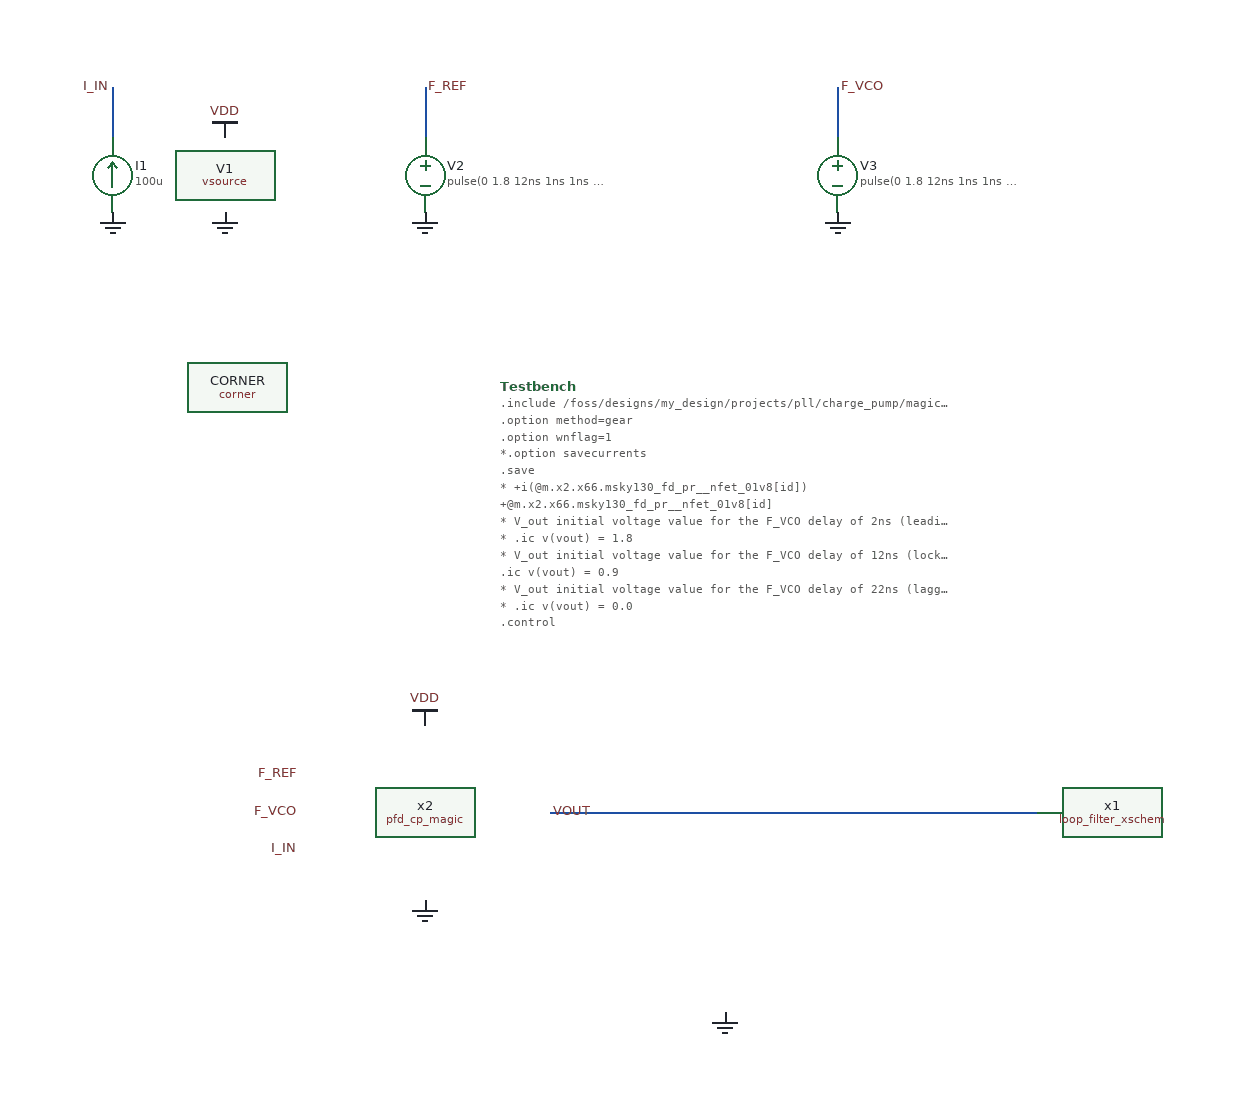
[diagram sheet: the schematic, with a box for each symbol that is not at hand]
v {xschem version=3.4.6 file_version=1.2}
G {}
K {}
V {}
S {}
E {}
B 2 3410 -4250 4770 -3590 {flags=graph
y1=0
y2=1.8
ypos1=0
ypos2=2
divy=5
subdivy=1
unity=1
x1=0
x2=2e-08
divx=5
subdivx=1
xlabmag=1.0
ylabmag=1.0


dataset=0
unitx=1
logx=0
logy=0








linewidth_mult=3







autoload=0
sim_type=tran
color="6 7"
node="f_ref
f_vco"}
B 2 3410 -2860 4790 -2180 {flags=graph
y1=0
y2=0.01
ypos1=0
ypos2=2
divy=5
subdivy=1
unity=1
x1=0
x2=2e-08
divx=5
subdivx=1
xlabmag=1.0
ylabmag=1.0


dataset=0
unitx=1
logx=0
logy=0








linewidth_mult=5





color="6 5"
node="up_pfd_b
down_pfd_b"}
B 2 3410 -3570 4790 -2870 {flags=graph
y1=0
y2=0.01
ypos1=0
ypos2=2
divy=5
subdivy=1
unity=1
x1=0
x2=2e-08
divx=5
subdivx=1
xlabmag=1.0
ylabmag=1.0


dataset=0
unitx=1
logx=0
logy=0








linewidth_mult=5

color="6 5"
node="up_pfd
down_pfd"}
B 2 3410 -2160 4790 -1480 {flags=graph
y1=0
y2=0.01
ypos1=0
ypos2=2
divy=5
subdivy=1
unity=1
x1=0
x2=2e-08
divx=5
subdivx=1
xlabmag=1.0
ylabmag=1.0


dataset=0
unitx=1
logx=0
logy=0








linewidth_mult=5





color="6 5"
node="up
down_b"}
B 2 3410 -1460 4790 -780 {flags=graph
y1=0
y2=0.01
ypos1=0
ypos2=2
divy=5
subdivy=1
unity=1
x1=0
x2=2e-08
divx=5
subdivx=1
xlabmag=1.0
ylabmag=1.0


dataset=0
unitx=1
logx=0
logy=0








linewidth_mult=5





color="6 5"
node="up_b
down"}
B 2 1860 -1670 3220 -1000 {flags=graph
y1=1.7
y2=1.9
ypos1=0
ypos2=2
divy=5
subdivy=1
unity=1
x1=0
x2=2e-08
divx=5
subdivx=1
xlabmag=1.0
ylabmag=1.0


dataset=0
unitx=1
logx=0
logy=0








linewidth_mult=7




color="5 5 5 5 5 5 5 5 5 5 5 5 5 5 5 5 5 5 5 5 5 5 5 5 5 5 5 5 5 5 5 5 5 5 5 5 5 5 5 5 5 5 5 5 5 5 5 5 5 5 5 5 5 5 5 5 5 5 5 5 5 5 5 5 5 5 5 5 5 5 5 5 5 5 5 5 5 5 5 5 5 5 5 5 5 5 5 5 5 5 5 5 5 5 5 5 5 5 5 5 5 5 5 5 5 5 5 5 5 5 5 5 5 5 5 5 5 5 5 5 5 5 5 5 5 5 5 5 5 5 5 5 5 5 5 5 5 5 5 5 5 5 5 5 5 5 5 5 5 5 5 5 5 5 5 5 5 5 5 5 5 5 5 5 5 5 5 5 5 5 5 5 5 5 5 5 5 5 5 5 5 5 5 5 5 5 5 5 5 5 5 5 5 5 5 5 5 5 5 5 5 5 5 5 5 5 5 5 5 5 5 5 5 5 5 5 5 5 5 5 5 5 5 5 5 5 5 5 5 5 5 5 5 5 5 5 5 5 5 5 5 5 5 5 5 5 5 5 5 5 5 5 5 5 5 5 5 5 5 5 5 5 5 5 5 5 5 5 5 5 5 5 5 5 5 5 5 5 5 5 5 5 5 5 5 5 5 5 5 5 5 5 5 5 5 5 5 5 5 5 5 5 5 5 5 5 5 5 5 5 5 5 5 5 5 5 5 5 5 5 5 5 5 5 5 5 5 5 5 5 5 5 5 5 5 5 5 5 5 5 5 5 5 5 5 5 5 5 5 5 5 5 5 5 5 5 5 5 5 5 5 5 5 5 5 5 5 5 5 5 5 5 5 5 5 5 5 5 5 5 5 5 5 5 5 5 5 5 5 5 5 5 5 5 5 5 5 5 5 5 5 5 5 5 5 5 5 5 5 5 5 5 5 5 5 5 5 5 5 5 5 5 5 5 5 5 5 5 5 5 5 5 5 5 5 5 5 5 5 5 5 5 5 5 5 5 5 5 5 5 5 5 5 5 5 5 5 5 5 5 5 5 5 5 5 5 5 5 5 5 5 5 5 5 5 5 5 5 5 5 5 5 5 5 5 5 5 5 5 5 5 5 5 5 5 5 5 5 5 5 5 5 5 5 5 5 5 5 5 5 5 5 5 5 5 5 5 5 5 5 5 5 5 5 5 5 5 5 5 5 5 5 5 5 5 5 5 5 5 5 5 5 5 5 5 5 5 5 5 5 5 5 5 5 5 5 5 5 5 5 5 5 5 5 5 5 5 5 5 5 5 5 5 5 5 5 5 5 5 5 5 5 5 5 5 5 5 5 5 5 5 5 5 5 5 5 5 5 5 5 5 5 5 5 5 5 5 5 5 5 5 5 5 5 5 5 5 5 5 5 5 5 5 5 5 5 5 5 5 5 5 5 5 5 5 5"
node="x2.vdda.t129
x2.vdda.t128
x2.vdda.t127
x2.vdda.t126
x2.vdda.t125
x2.vdda.t124
x2.vdda.t123
x2.vdda.t122
x2.vdda.t121
x2.vdda.t120
x2.vdda.t119
x2.vdda.t118
x2.vdda.t117
x2.vdda.t116
x2.vdda.t115
x2.vdda.t114
x2.vdda.t113
x2.vdda.t112
x2.vdda.t111
x2.vdda.t110
x2.vdda.t109
x2.vdda.t108
x2.vdda.t107
x2.vdda.t106
x2.vdda.t105
x2.vdda.t104
x2.vdda.t103
x2.vdda.t102
x2.vdda.t101
x2.vdda.t100
x2.vdda.t99
x2.vdda.t98
x2.vdda.t97
x2.vdda.t96
x2.vdda.t95
x2.vdda.t94
x2.vdda.t93
x2.vdda.t92
x2.vdda.t91
x2.vdda.t90
x2.vdda.t89
x2.vdda.t88
x2.vdda.t87
x2.vdda.t86
x2.vdda.t85
x2.vdda.t84
x2.vdda.t83
x2.vdda.t82
x2.vdda.t81
x2.vdda.t80
x2.vdda.t79
x2.vdda.t78
x2.vdda.t77
x2.vdda.t76
x2.vdda.t75
x2.vdda.t74
x2.vdda.t73
x2.vdda.t72
x2.vdda.t71
x2.vdda.t70
x2.vdda.t69
x2.vdda.t68
x2.vdda.t67
x2.vdda.t66
x2.vdda.t65
x2.vdda.t64
x2.vdda.t63
x2.vdda.t62
x2.vdda.t61
x2.vdda.t60
x2.vdda.t59
x2.vdda.t58
x2.vdda.t57
x2.vdda.t56
x2.vdda.t55
x2.vdda.t54
x2.vdda.t53
x2.vdda.t52
x2.vdda.t51
x2.vdda.t50
x2.vdda.t49
x2.vdda.t48
x2.vdda.t47
x2.vdda.t46
x2.vdda.t45
x2.vdda.t44
x2.vdda.t43
x2.vdda.t42
x2.vdda.t41
x2.vdda.t40
x2.vdda.t39
x2.vdda.t38
x2.vdda.t37
x2.vdda.t36
x2.vdda.t35
x2.vdda.t34
x2.vdda.t33
x2.vdda.t32
x2.vdda.t31
x2.vdda.t30
x2.vdda.t29
x2.vdda.t28
x2.vdda.t27
x2.vdda.t26
x2.vdda.t25
x2.vdda.t24
x2.vdda.t23
x2.vdda.t22
x2.vdda.t21
x2.vdda.t20
x2.vdda.t19
x2.vdda.t18
x2.vdda.t17
x2.vdda.t16
x2.vdda.t15
x2.vdda.t14
x2.vdda.t13
x2.vdda.t12
x2.vdda.t11
x2.vdda.t10
x2.vdda.t9
x2.vdda.t8
x2.vdda.t7
x2.vdda.t6
x2.vdda.t5
x2.vdda.t4
x2.vdda.t3
x2.vdda.t2
x2.vdda.t1
x2.vdda.t0
x2.vdda.n505
x2.vdda.n504
x2.vdda.n503
x2.vdda.n502
x2.vdda.n501
x2.vdda.n500
x2.vdda.n499
x2.vdda.n498
x2.vdda.n497
x2.vdda.n496
x2.vdda.n495
x2.vdda.n494
x2.vdda.n493
x2.vdda.n492
x2.vdda.n491
x2.vdda.n490
x2.vdda.n489
x2.vdda.n488
x2.vdda.n487
x2.vdda.n486
x2.vdda.n485
x2.vdda.n484
x2.vdda.n483
x2.vdda.n482
x2.vdda.n481
x2.vdda.n480
x2.vdda.n479
x2.vdda.n478
x2.vdda.n477
x2.vdda.n476
x2.vdda.n475
x2.vdda.n474
x2.vdda.n473
x2.vdda.n472
x2.vdda.n471
x2.vdda.n470
x2.vdda.n469
x2.vdda.n468
x2.vdda.n467
x2.vdda.n466
x2.vdda.n465
x2.vdda.n464
x2.vdda.n463
x2.vdda.n462
x2.vdda.n461
x2.vdda.n460
x2.vdda.n459
x2.vdda.n458
x2.vdda.n457
x2.vdda.n456
x2.vdda.n455
x2.vdda.n454
x2.vdda.n453
x2.vdda.n452
x2.vdda.n451
x2.vdda.n450
x2.vdda.n449
x2.vdda.n448
x2.vdda.n447
x2.vdda.n446
x2.vdda.n445
x2.vdda.n444
x2.vdda.n443
x2.vdda.n442
x2.vdda.n441
x2.vdda.n440
x2.vdda.n439
x2.vdda.n438
x2.vdda.n437
x2.vdda.n436
x2.vdda.n435
x2.vdda.n434
x2.vdda.n433
x2.vdda.n432
x2.vdda.n431
x2.vdda.n430
x2.vdda.n429
x2.vdda.n428
x2.vdda.n427
x2.vdda.n426
x2.vdda.n425
x2.vdda.n424
x2.vdda.n423
x2.vdda.n422
x2.vdda.n421
x2.vdda.n420
x2.vdda.n419
x2.vdda.n418
x2.vdda.n417
x2.vdda.n416
x2.vdda.n415
x2.vdda.n414
x2.vdda.n413
x2.vdda.n412
x2.vdda.n411
x2.vdda.n410
x2.vdda.n409
x2.vdda.n408
x2.vdda.n407
x2.vdda.n406
x2.vdda.n405
x2.vdda.n404
x2.vdda.n403
x2.vdda.n402
x2.vdda.n401
x2.vdda.n400
x2.vdda.n399
x2.vdda.n398
x2.vdda.n397
x2.vdda.n396
x2.vdda.n395
x2.vdda.n394
x2.vdda.n393
x2.vdda.n392
x2.vdda.n391
x2.vdda.n390
x2.vdda.n389
x2.vdda.n388
x2.vdda.n387
x2.vdda.n386
x2.vdda.n385
x2.vdda.n384
x2.vdda.n383
x2.vdda.n382
x2.vdda.n381
x2.vdda.n380
x2.vdda.n379
x2.vdda.n378
x2.vdda.n377
x2.vdda.n376
x2.vdda.n375
x2.vdda.n374
x2.vdda.n373
x2.vdda.n372
x2.vdda.n371
x2.vdda.n370
x2.vdda.n369
x2.vdda.n368
x2.vdda.n367
x2.vdda.n366
x2.vdda.n365
x2.vdda.n364
x2.vdda.n363
x2.vdda.n362
x2.vdda.n361
x2.vdda.n360
x2.vdda.n359
x2.vdda.n358
x2.vdda.n357
x2.vdda.n356
x2.vdda.n355
x2.vdda.n354
x2.vdda.n353
x2.vdda.n352
x2.vdda.n351
x2.vdda.n350
x2.vdda.n349
x2.vdda.n348
x2.vdda.n347
x2.vdda.n346
x2.vdda.n345
x2.vdda.n344
x2.vdda.n343
x2.vdda.n342
x2.vdda.n341
x2.vdda.n340
x2.vdda.n339
x2.vdda.n338
x2.vdda.n337
x2.vdda.n336
x2.vdda.n335
x2.vdda.n334
x2.vdda.n333
x2.vdda.n332
x2.vdda.n331
x2.vdda.n330
x2.vdda.n329
x2.vdda.n328
x2.vdda.n327
x2.vdda.n326
x2.vdda.n325
x2.vdda.n324
x2.vdda.n323
x2.vdda.n322
x2.vdda.n321
x2.vdda.n320
x2.vdda.n319
x2.vdda.n318
x2.vdda.n317
x2.vdda.n316
x2.vdda.n315
x2.vdda.n314
x2.vdda.n313
x2.vdda.n312
x2.vdda.n311
x2.vdda.n310
x2.vdda.n309
x2.vdda.n308
x2.vdda.n307
x2.vdda.n306
x2.vdda.n305
x2.vdda.n304
x2.vdda.n303
x2.vdda.n302
x2.vdda.n301
x2.vdda.n300
x2.vdda.n299
x2.vdda.n298
x2.vdda.n297
x2.vdda.n296
x2.vdda.n295
x2.vdda.n294
x2.vdda.n293
x2.vdda.n292
x2.vdda.n291
x2.vdda.n290
x2.vdda.n289
x2.vdda.n288
x2.vdda.n287
x2.vdda.n286
x2.vdda.n285
x2.vdda.n284
x2.vdda.n283
x2.vdda.n282
x2.vdda.n281
x2.vdda.n280
x2.vdda.n279
x2.vdda.n278
x2.vdda.n277
x2.vdda.n276
x2.vdda.n275
x2.vdda.n274
x2.vdda.n273
x2.vdda.n272
x2.vdda.n271
x2.vdda.n270
x2.vdda.n269
x2.vdda.n268
x2.vdda.n267
x2.vdda.n266
x2.vdda.n265
x2.vdda.n264
x2.vdda.n263
x2.vdda.n262
x2.vdda.n261
x2.vdda.n260
x2.vdda.n259
x2.vdda.n258
x2.vdda.n257
x2.vdda.n256
x2.vdda.n255
x2.vdda.n254
x2.vdda.n253
x2.vdda.n252
x2.vdda.n251
x2.vdda.n250
x2.vdda.n249
x2.vdda.n248
x2.vdda.n247
x2.vdda.n246
x2.vdda.n245
x2.vdda.n244
x2.vdda.n243
x2.vdda.n242
x2.vdda.n241
x2.vdda.n240
x2.vdda.n239
x2.vdda.n238
x2.vdda.n237
x2.vdda.n236
x2.vdda.n235
x2.vdda.n234
x2.vdda.n233
x2.vdda.n232
x2.vdda.n231
x2.vdda.n230
x2.vdda.n229
x2.vdda.n228
x2.vdda.n227
x2.vdda.n226
x2.vdda.n225
x2.vdda.n224
x2.vdda.n223
x2.vdda.n222
x2.vdda.n221
x2.vdda.n220
x2.vdda.n219
x2.vdda.n218
x2.vdda.n217
x2.vdda.n216
x2.vdda.n215
x2.vdda.n214
x2.vdda.n213
x2.vdda.n212
x2.vdda.n211
x2.vdda.n210
x2.vdda.n209
x2.vdda.n208
x2.vdda.n207
x2.vdda.n206
x2.vdda.n205
x2.vdda.n204
x2.vdda.n203
x2.vdda.n202
x2.vdda.n201
x2.vdda.n200
x2.vdda.n199
x2.vdda.n198
x2.vdda.n197
x2.vdda.n196
x2.vdda.n195
x2.vdda.n194
x2.vdda.n193
x2.vdda.n192
x2.vdda.n191
x2.vdda.n190
x2.vdda.n189
x2.vdda.n188
x2.vdda.n187
x2.vdda.n186
x2.vdda.n185
x2.vdda.n184
x2.vdda.n183
x2.vdda.n182
x2.vdda.n181
x2.vdda.n180
x2.vdda.n179
x2.vdda.n178
x2.vdda.n177
x2.vdda.n176
x2.vdda.n175
x2.vdda.n174
x2.vdda.n173
x2.vdda.n172
x2.vdda.n171
x2.vdda.n170
x2.vdda.n169
x2.vdda.n168
x2.vdda.n167
x2.vdda.n166
x2.vdda.n165
x2.vdda.n164
x2.vdda.n163
x2.vdda.n162
x2.vdda.n161
x2.vdda.n160
x2.vdda.n159
x2.vdda.n158
x2.vdda.n157
x2.vdda.n156
x2.vdda.n155
x2.vdda.n154
x2.vdda.n153
x2.vdda.n152
x2.vdda.n151
x2.vdda.n150
x2.vdda.n149
x2.vdda.n148
x2.vdda.n147
x2.vdda.n146
x2.vdda.n145
x2.vdda.n144
x2.vdda.n143
x2.vdda.n142
x2.vdda.n141
x2.vdda.n140
x2.vdda.n139
x2.vdda.n138
x2.vdda.n137
x2.vdda.n136
x2.vdda.n135
x2.vdda.n134
x2.vdda.n133
x2.vdda.n132
x2.vdda.n131
x2.vdda.n130
x2.vdda.n129
x2.vdda.n128
x2.vdda.n127
x2.vdda.n126
x2.vdda.n125
x2.vdda.n124
x2.vdda.n123
x2.vdda.n122
x2.vdda.n121
x2.vdda.n120
x2.vdda.n119
x2.vdda.n118
x2.vdda.n117
x2.vdda.n116
x2.vdda.n115
x2.vdda.n114
x2.vdda.n113
x2.vdda.n112
x2.vdda.n111
x2.vdda.n110
x2.vdda.n109
x2.vdda.n108
x2.vdda.n107
x2.vdda.n106
x2.vdda.n105
x2.vdda.n104
x2.vdda.n103
x2.vdda.n102
x2.vdda.n101
x2.vdda.n100
x2.vdda.n99
x2.vdda.n98
x2.vdda.n97
x2.vdda.n96
x2.vdda.n95
x2.vdda.n94
x2.vdda.n93
x2.vdda.n92
x2.vdda.n91
x2.vdda.n90
x2.vdda.n89
x2.vdda.n88
x2.vdda.n87
x2.vdda.n86
x2.vdda.n85
x2.vdda.n84
x2.vdda.n83
x2.vdda.n82
x2.vdda.n81
x2.vdda.n80
x2.vdda.n79
x2.vdda.n78
x2.vdda.n77
x2.vdda.n76
x2.vdda.n75
x2.vdda.n74
x2.vdda.n73
x2.vdda.n72
x2.vdda.n71
x2.vdda.n70
x2.vdda.n69
x2.vdda.n68
x2.vdda.n67
x2.vdda.n66
x2.vdda.n65
x2.vdda.n64
x2.vdda.n63
x2.vdda.n62
x2.vdda.n61
x2.vdda.n60
x2.vdda.n59
x2.vdda.n58
x2.vdda.n57
x2.vdda.n56
x2.vdda.n55
x2.vdda.n54
x2.vdda.n53
x2.vdda.n52
x2.vdda.n51
x2.vdda.n50
x2.vdda.n49
x2.vdda.n48
x2.vdda.n47
x2.vdda.n46
x2.vdda.n45
x2.vdda.n44
x2.vdda.n43
x2.vdda.n42
x2.vdda.n41
x2.vdda.n40
x2.vdda.n39
x2.vdda.n38
x2.vdda.n37
x2.vdda.n36
x2.vdda.n35
x2.vdda.n34
x2.vdda.n33
x2.vdda.n32
x2.vdda.n31
x2.vdda.n30
x2.vdda.n29
x2.vdda.n28
x2.vdda.n27
x2.vdda.n26
x2.vdda.n25
x2.vdda.n24
x2.vdda.n23
x2.vdda.n22
x2.vdda.n21
x2.vdda.n20
x2.vdda.n19
x2.vdda.n18
x2.vdda.n17
x2.vdda.n16
x2.vdda.n15
x2.vdda.n14
x2.vdda.n13
x2.vdda.n12
x2.vdda.n11
x2.vdda.n10
x2.vdda.n9
x2.vdda.n8
x2.vdda.n7
x2.vdda.n6
x2.vdda.n5
x2.vdda.n4
x2.vdda.n3
x2.vdda.n2
x2.vdda.n1
x2.vdda.n0"}
B 2 1860 -2370 3220 -1700 {flags=graph
y1=-0.045
y2=0.064
ypos1=0
ypos2=2
divy=5
subdivy=1
unity=1
x1=0
x2=2e-08
divx=5
subdivx=1
xlabmag=1.0
ylabmag=1.0


dataset=0
unitx=1
logx=0
logy=0








linewidth_mult=7




color="5 5 5 5 5 5 5 5 5 5 5 5 5 5 5 5 5 5 5 5 5 5 5 5 5 5 5 5 5 5 5 5 5 5 5 5 5 5 5 5 5 5 5 5 5 5 5 5 5 5 5 5 5 5 5 5 5 5 5 5 5 5 5 5 5 5 5 5 5 5 5 5 5 5 5 5 5 5 5 5 5 5 5 5 5 5 5 5 5 5 5 5 5 5 5 5 5 5 5 5 5 5 5 5 5 5 5 5 5 5 5 5 5 5 5 5 5 5 5 5 5 5 5 5 5 5 5 5 5 5 5 5 5 5 5 5 5 5 5 5 5 5 5 5 5 5 5 5 5 5 5 5 5 5 5 5 5 5 5 5 5 5 5 5 5 5 5 5 5 5 5 5 5 5 5 5 5 5 5 5 5 5 5 5 5 5 5 5 5 5 5 5 5 5 5 5 5 5 5 5 5 5 5 5 5 5 5 5 5 5 5 5 5 5 5 5 5 5 5 5 5 5 5 5 5 5 5 5 5 5 5 5 5 5 5 5 5 5 5 5 5 5 5 5 5 5 5 5 5 5 5 5 5 5 5 5 5 5 5 5 5 5 5 5 5 5 5 5 5 5 5 5 5 5 5 5 5 5 5 5 5 5 5 5 5 5 5 5 5 5 5 5 5 5 5 5 5 5 5 5 5 5 5 5 5 5 5 5 5 5 5 5 5 5 5 5 5 5 5 5 5 5 5 5 5 5 5 5 5 5 5 5 5 5 5 5 5 5 5 5 5 5 5 5 5 5 5 5 5 5 5 5 5 5 5 5 5 5 5 5 5 5 5 5 5 5 5 5 5 5 5 5 5 5 5 5 5 5 5 5 5 5 5 5 5 5 5 5 5 5 5 5 5 5 5 5 5 5 5 5 5 5 5 5 5 5 5 5 5 5 5 5 5 5 5 5 5 5 5 5 5 5 5 5 5 5 5 5 5 5 5 5 5 5 5 5 5 5 5 5 5 5 5 5 5 5 5 5 5 5 5 5 5 5 5 5 5 5 5 5 5 5 5 5 5 5 5 5 5 5 5 5 5 5 5 5 5 5 5 5 5 5 5 5 5 5 5 5 5 5 5 5 5 5 5 5 5 5 5 5 5 5 5 5 5 5 5 5 5 5 5 5 5 5 5 5 5 5 5 5 5 5 5 5 5 5 5 5 5 5 5 5 5 5 5 5 5 5 5 5 5 5 5 5 5 5 5 5 5 5 5 5 5 5 5 5 5 5 5 5 5 5 5 5 5 5 5 5 5 5 5 5 5 5 5 5 5 5 5 5 5 5 5 5 5 5 5 5 5 5 5 5 5 5 5 5 5 5 5 5 5 5 5"
node="x2.gnda.t155
x2.gnda.t154
x2.gnda.t153
x2.gnda.t152
x2.gnda.t151
x2.gnda.t150
x2.gnda.t149
x2.gnda.t148
x2.gnda.t147
x2.gnda.t146
x2.gnda.t145
x2.gnda.t144
x2.gnda.t143
x2.gnda.t142
x2.gnda.t141
x2.gnda.t140
x2.gnda.t139
x2.gnda.t138
x2.gnda.t137
x2.gnda.t136
x2.gnda.t135
x2.gnda.t134
x2.gnda.t133
x2.gnda.t132
x2.gnda.t131
x2.gnda.t130
x2.gnda.t129
x2.gnda.t128
x2.gnda.t127
x2.gnda.t126
x2.gnda.t125
x2.gnda.t124
x2.gnda.t123
x2.gnda.t122
x2.gnda.t121
x2.gnda.t120
x2.gnda.t119
x2.gnda.t118
x2.gnda.t117
x2.gnda.t116
x2.gnda.t115
x2.gnda.t114
x2.gnda.t113
x2.gnda.t112
x2.gnda.t111
x2.gnda.t110
x2.gnda.t109
x2.gnda.t108
x2.gnda.t107
x2.gnda.t106
x2.gnda.t105
x2.gnda.t104
x2.gnda.t103
x2.gnda.t102
x2.gnda.t101
x2.gnda.t100
x2.gnda.t99
x2.gnda.t98
x2.gnda.t97
x2.gnda.t96
x2.gnda.t95
x2.gnda.t94
x2.gnda.t93
x2.gnda.t92
x2.gnda.t91
x2.gnda.t90
x2.gnda.t89
x2.gnda.t88
x2.gnda.t87
x2.gnda.t86
x2.gnda.t85
x2.gnda.t84
x2.gnda.t83
x2.gnda.t82
x2.gnda.t81
x2.gnda.t80
x2.gnda.t79
x2.gnda.t78
x2.gnda.t77
x2.gnda.t76
x2.gnda.t75
x2.gnda.t74
x2.gnda.t73
x2.gnda.t72
x2.gnda.t71
x2.gnda.t70
x2.gnda.t69
x2.gnda.t68
x2.gnda.t67
x2.gnda.t66
x2.gnda.t65
x2.gnda.t64
x2.gnda.t63
x2.gnda.t62
x2.gnda.t61
x2.gnda.t60
x2.gnda.t59
x2.gnda.t58
x2.gnda.t57
x2.gnda.t56
x2.gnda.t55
x2.gnda.t54
x2.gnda.t53
x2.gnda.t52
x2.gnda.t51
x2.gnda.t50
x2.gnda.t49
x2.gnda.t48
x2.gnda.t47
x2.gnda.t46
x2.gnda.t45
x2.gnda.t44
x2.gnda.t43
x2.gnda.t42
x2.gnda.t41
x2.gnda.t40
x2.gnda.t39
x2.gnda.t38
x2.gnda.t37
x2.gnda.t36
x2.gnda.t35
x2.gnda.t34
x2.gnda.t33
x2.gnda.t32
x2.gnda.t31
x2.gnda.t30
x2.gnda.t29
x2.gnda.t28
x2.gnda.t27
x2.gnda.t26
x2.gnda.t25
x2.gnda.t24
x2.gnda.t23
x2.gnda.t22
x2.gnda.t21
x2.gnda.t20
x2.gnda.t19
x2.gnda.t18
x2.gnda.t17
x2.gnda.t16
x2.gnda.t15
x2.gnda.t14
x2.gnda.t13
x2.gnda.t12
x2.gnda.t11
x2.gnda.t10
x2.gnda.t9
x2.gnda.t8
x2.gnda.t7
x2.gnda.t6
x2.gnda.t5
x2.gnda.t4
x2.gnda.t3
x2.gnda.t2
x2.gnda.t1
x2.gnda.t0
x2.gnda.n446
x2.gnda.n445
x2.gnda.n444
x2.gnda.n443
x2.gnda.n442
x2.gnda.n441
x2.gnda.n440
x2.gnda.n439
x2.gnda.n438
x2.gnda.n437
x2.gnda.n436
x2.gnda.n435
x2.gnda.n434
x2.gnda.n433
x2.gnda.n432
x2.gnda.n431
x2.gnda.n430
x2.gnda.n429
x2.gnda.n428
x2.gnda.n427
x2.gnda.n426
x2.gnda.n425
x2.gnda.n424
x2.gnda.n423
x2.gnda.n422
x2.gnda.n421
x2.gnda.n420
x2.gnda.n419
x2.gnda.n418
x2.gnda.n417
x2.gnda.n416
x2.gnda.n415
x2.gnda.n414
x2.gnda.n413
x2.gnda.n412
x2.gnda.n411
x2.gnda.n410
x2.gnda.n409
x2.gnda.n408
x2.gnda.n407
x2.gnda.n406
x2.gnda.n405
x2.gnda.n404
x2.gnda.n403
x2.gnda.n402
x2.gnda.n401
x2.gnda.n400
x2.gnda.n399
x2.gnda.n398
x2.gnda.n397
x2.gnda.n396
x2.gnda.n395
x2.gnda.n394
x2.gnda.n393
x2.gnda.n392
x2.gnda.n391
x2.gnda.n390
x2.gnda.n389
x2.gnda.n388
x2.gnda.n387
x2.gnda.n386
x2.gnda.n385
x2.gnda.n384
x2.gnda.n383
x2.gnda.n382
x2.gnda.n381
x2.gnda.n380
x2.gnda.n379
x2.gnda.n378
x2.gnda.n377
x2.gnda.n376
x2.gnda.n375
x2.gnda.n374
x2.gnda.n373
x2.gnda.n372
x2.gnda.n371
x2.gnda.n370
x2.gnda.n369
x2.gnda.n368
x2.gnda.n367
x2.gnda.n366
x2.gnda.n365
x2.gnda.n364
x2.gnda.n363
x2.gnda.n362
x2.gnda.n361
x2.gnda.n360
x2.gnda.n359
x2.gnda.n358
x2.gnda.n357
x2.gnda.n356
x2.gnda.n355
x2.gnda.n354
x2.gnda.n353
x2.gnda.n352
x2.gnda.n351
x2.gnda.n350
x2.gnda.n349
x2.gnda.n348
x2.gnda.n347
x2.gnda.n346
x2.gnda.n345
x2.gnda.n344
x2.gnda.n343
x2.gnda.n342
x2.gnda.n341
x2.gnda.n340
x2.gnda.n339
x2.gnda.n338
x2.gnda.n337
x2.gnda.n336
x2.gnda.n335
x2.gnda.n334
x2.gnda.n333
x2.gnda.n332
x2.gnda.n331
x2.gnda.n330
x2.gnda.n329
x2.gnda.n328
x2.gnda.n327
x2.gnda.n326
x2.gnda.n325
x2.gnda.n324
x2.gnda.n323
x2.gnda.n322
x2.gnda.n321
x2.gnda.n320
x2.gnda.n319
x2.gnda.n318
x2.gnda.n317
x2.gnda.n316
x2.gnda.n315
x2.gnda.n314
x2.gnda.n313
x2.gnda.n312
x2.gnda.n311
x2.gnda.n310
x2.gnda.n309
x2.gnda.n308
x2.gnda.n307
x2.gnda.n306
x2.gnda.n305
x2.gnda.n304
x2.gnda.n303
x2.gnda.n302
x2.gnda.n301
x2.gnda.n300
x2.gnda.n299
x2.gnda.n298
x2.gnda.n297
x2.gnda.n296
x2.gnda.n295
x2.gnda.n294
x2.gnda.n293
x2.gnda.n292
x2.gnda.n291
x2.gnda.n290
x2.gnda.n289
x2.gnda.n288
x2.gnda.n287
x2.gnda.n286
x2.gnda.n285
x2.gnda.n284
x2.gnda.n283
x2.gnda.n282
x2.gnda.n281
x2.gnda.n280
x2.gnda.n279
x2.gnda.n278
x2.gnda.n277
x2.gnda.n276
x2.gnda.n275
x2.gnda.n274
x2.gnda.n273
x2.gnda.n272
x2.gnda.n271
x2.gnda.n270
x2.gnda.n269
x2.gnda.n268
x2.gnda.n267
x2.gnda.n266
x2.gnda.n265
x2.gnda.n264
x2.gnda.n263
x2.gnda.n262
x2.gnda.n261
x2.gnda.n260
x2.gnda.n259
x2.gnda.n258
x2.gnda.n257
x2.gnda.n256
x2.gnda.n255
x2.gnda.n254
x2.gnda.n253
x2.gnda.n252
x2.gnda.n251
x2.gnda.n250
x2.gnda.n249
x2.gnda.n248
x2.gnda.n247
x2.gnda.n246
x2.gnda.n245
x2.gnda.n244
x2.gnda.n243
x2.gnda.n242
x2.gnda.n241
x2.gnda.n240
x2.gnda.n239
x2.gnda.n238
x2.gnda.n237
x2.gnda.n236
x2.gnda.n235
x2.gnda.n234
x2.gnda.n233
x2.gnda.n232
x2.gnda.n231
x2.gnda.n230
x2.gnda.n229
x2.gnda.n228
x2.gnda.n227
x2.gnda.n226
x2.gnda.n225
x2.gnda.n224
x2.gnda.n223
x2.gnda.n222
x2.gnda.n221
x2.gnda.n220
x2.gnda.n219
x2.gnda.n218
x2.gnda.n217
x2.gnda.n216
x2.gnda.n215
x2.gnda.n214
x2.gnda.n213
x2.gnda.n212
x2.gnda.n211
x2.gnda.n210
x2.gnda.n209
x2.gnda.n208
x2.gnda.n207
x2.gnda.n206
x2.gnda.n205
x2.gnda.n204
x2.gnda.n203
x2.gnda.n202
x2.gnda.n201
x2.gnda.n200
x2.gnda.n199
x2.gnda.n198
x2.gnda.n197
x2.gnda.n196
x2.gnda.n195
x2.gnda.n194
x2.gnda.n193
x2.gnda.n192
x2.gnda.n191
x2.gnda.n190
x2.gnda.n189
x2.gnda.n188
x2.gnda.n187
x2.gnda.n186
x2.gnda.n185
x2.gnda.n184
x2.gnda.n183
x2.gnda.n182
x2.gnda.n181
x2.gnda.n180
x2.gnda.n179
x2.gnda.n178
x2.gnda.n177
x2.gnda.n176
x2.gnda.n175
x2.gnda.n174
x2.gnda.n173
x2.gnda.n172
x2.gnda.n171
x2.gnda.n170
x2.gnda.n169
x2.gnda.n168
x2.gnda.n167
x2.gnda.n166
x2.gnda.n165
x2.gnda.n164
x2.gnda.n163
x2.gnda.n162
x2.gnda.n161
x2.gnda.n160
x2.gnda.n159
x2.gnda.n158
x2.gnda.n157
x2.gnda.n156
x2.gnda.n155
x2.gnda.n154
x2.gnda.n153
x2.gnda.n152
x2.gnda.n151
x2.gnda.n150
x2.gnda.n149
x2.gnda.n148
x2.gnda.n147
x2.gnda.n146
x2.gnda.n145
x2.gnda.n144
x2.gnda.n143
x2.gnda.n142
x2.gnda.n141
x2.gnda.n140
x2.gnda.n139
x2.gnda.n138
x2.gnda.n137
x2.gnda.n136
x2.gnda.n135
x2.gnda.n134
x2.gnda.n133
x2.gnda.n132
x2.gnda.n131
x2.gnda.n130
x2.gnda.n129
x2.gnda.n128
x2.gnda.n127
x2.gnda.n126
x2.gnda.n125
x2.gnda.n124
x2.gnda.n123
x2.gnda.n122
x2.gnda.n121
x2.gnda.n120
x2.gnda.n119
x2.gnda.n118
x2.gnda.n117
x2.gnda.n116
x2.gnda.n115
x2.gnda.n114
x2.gnda.n113
x2.gnda.n112
x2.gnda.n111
x2.gnda.n110
x2.gnda.n109
x2.gnda.n108
x2.gnda.n107
x2.gnda.n106
x2.gnda.n105
x2.gnda.n104
x2.gnda.n103
x2.gnda.n102
x2.gnda.n101
x2.gnda.n100
x2.gnda.n99
x2.gnda.n98
x2.gnda.n97
x2.gnda.n96
x2.gnda.n95
x2.gnda.n94
x2.gnda.n93
x2.gnda.n92
x2.gnda.n91
x2.gnda.n90
x2.gnda.n89
x2.gnda.n88
x2.gnda.n87
x2.gnda.n86
x2.gnda.n85
x2.gnda.n84
x2.gnda.n83
x2.gnda.n82
x2.gnda.n81
x2.gnda.n80
x2.gnda.n79
x2.gnda.n78
x2.gnda.n77
x2.gnda.n76
x2.gnda.n75
x2.gnda.n74
x2.gnda.n73
x2.gnda.n72
x2.gnda.n71
x2.gnda.n70
x2.gnda.n69
x2.gnda.n68
x2.gnda.n67
x2.gnda.n66
x2.gnda.n65
x2.gnda.n64
x2.gnda.n63
x2.gnda.n62
x2.gnda.n61
x2.gnda.n60
x2.gnda.n59
x2.gnda.n58
x2.gnda.n57
x2.gnda.n56
x2.gnda.n55
x2.gnda.n54
x2.gnda.n53
x2.gnda.n52
x2.gnda.n51
x2.gnda.n50
x2.gnda.n49
x2.gnda.n48
x2.gnda.n47
x2.gnda.n46
x2.gnda.n45
x2.gnda.n44
x2.gnda.n43
x2.gnda.n42
x2.gnda.n41
x2.gnda.n40
x2.gnda.n39
x2.gnda.n38
x2.gnda.n37
x2.gnda.n36
x2.gnda.n35
x2.gnda.n34
x2.gnda.n33
x2.gnda.n32
x2.gnda.n31
x2.gnda.n30
x2.gnda.n29
x2.gnda.n28
x2.gnda.n27
x2.gnda.n26
x2.gnda.n25
x2.gnda.n24
x2.gnda.n23
x2.gnda.n22
x2.gnda.n21
x2.gnda.n20
x2.gnda.n19
x2.gnda.n18
x2.gnda.n17
x2.gnda.n16
x2.gnda.n15
x2.gnda.n14
x2.gnda.n13
x2.gnda.n12
x2.gnda.n11
x2.gnda.n10
x2.gnda.n9
x2.gnda.n8
x2.gnda.n7
x2.gnda.n6
x2.gnda.n5
x2.gnda.n4
x2.gnda.n3
x2.gnda.n2
x2.gnda.n1
x2.gnda.n0"}
B 2 1860 -970 3220 -300 {flags=graph
y1=0
y2=0.01
ypos1=0
ypos2=2
divy=5
subdivy=1
unity=1
x1=0
x2=2e-08
divx=5
subdivx=1
xlabmag=1.0
ylabmag=1.0


dataset=0
unitx=1
logx=0
logy=0








linewidth_mult=7




color="6 5 6"
node="i(vmeas2)
i(vmeas3)
i(@m.x2.x66.msky130_fd_pr__nfet_01v8[id])"}
B 2 3420 -740 4800 -60 {flags=graph
y1=0
y2=0.01
ypos1=0
ypos2=2
divy=5
subdivy=1
unity=1
x1=0
x2=2e-08
divx=5
subdivx=1
xlabmag=1.0
ylabmag=1.0


dataset=0
unitx=1
logx=0
logy=0








linewidth_mult=5





color="6 5"
node="up_input
down_input"}
N 2470 -3430 2470 -3390 {
lab=F_REF}
N 2800 -3430 2800 -3390 {
lab=F_VCO}
N 2220 -3430 2220 -3390 {
lab=I_IN}
N 2570 -2850 2960 -2850 {lab=VOUT}
C {sky130_fd_pr/corner.sym} 2320 -3190 0 0 {name=CORNER only_toplevel=false corner=tt}
C {devices/code.sym} 2530 -3191.25 0 0 {name=Testbench only_toplevel=false value="

.include /foss/designs/my_design/projects/pll/charge_pump/magic/pfd_cp_magic.spice

.option method=gear
.option wnflag=1
*.option savecurrents

.save
* +i(@m.x2.x66.msky130_fd_pr__nfet_01v8[id])
+@m.x2.x66.msky130_fd_pr__nfet_01v8[id]


* V_out initial voltage value for the F_VCO delay of 2ns  (leading)
* .ic v(vout) = 1.8

* V_out initial voltage value for the F_VCO delay of 12ns (lock condition)
.ic v(vout) = 0.9

* V_out initial voltage value for the F_VCO delay of 22ns (lagging)
* .ic v(vout) = 0.0

.control
  * save v(f_ref) save v(f_vco) save v(i_in) save v(up_pfd) v(down_pfd) v(up_pfd_b) v(down_pfd_b) v(up) v(up_b) v(down) v(down_b) v(x) v(opamp_out) v(up_input) v(down_input) v(down_gate) v(vout)
  save all

  * timestep for exact simulation results
  * tran 5ps 0.5us

  * timestep for faster simulation results
  tran 50ps 0.02us

  remzerovec
  write pfd_charge_pump_magic.raw
  set appendwrite

.endc

"
}
C {devices/vsource.sym} 2310 -3360 0 0 {name=V1 value=1.8 savecurrent=false}
C {devices/gnd.sym} 2310 -3330 0 0 {name=l2 lab=GND}
C {devices/vdd.sym} 2310 -3390 0 1 {name=l3 lab=VDD}
C {devices/vsource.sym} 2470 -3360 0 0 {name=V2 value=pulse"(0 1.8 12ns 1ns 1ns 24ns 50ns)" savecurrent=false
* }
C {devices/gnd.sym} 2470 -3330 0 0 {name=l10 lab=GND}
C {devices/lab_pin.sym} 2470 -3430 0 1 {name=p11 sig_type=std_logic lab=F_REF}
C {devices/vsource.sym} 2800 -3360 0 0 {name=V3 value="pulse(0 1.8 12ns 1ns 1ns 24ns 50ns)" savecurrent=false}
C {devices/gnd.sym} 2800 -3330 0 0 {name=l15 lab=GND}
C {devices/lab_pin.sym} 2800 -3430 0 1 {name=p12 sig_type=std_logic lab=F_VCO}
C {devices/lab_pin.sym} 2370 -2880 0 0 {name=p19 lab=F_REF
value="

.include /foss/pdks/sky130A/libs.ref/sky130_fd_sc_hd/spice/sky130_fd_sc_hd.spice

.option method=gear
.option wnflag=1

* V_out initial voltage value for the F_VCO delay of 2ns  (leading)
* .ic v(vout) = 1.8

* V_out initial voltage value for the F_VCO delay of 12ns (lock condition)
.ic v(vout) = 0.83

* V_out initial voltage value for the F_VCO delay of 22ns (lagging)
* .ic v(vout) = 0

.control
  save v(f_ref) save v(f_vco) save v(i_in) save v(up_pfd) v(down_pfd) v(up_pfd_b) v(down_pfd_b) v(up) v(up_b) v(down) v(down_b) v(x) v(opamp_out) v(up_input) v(down_input) v(down_gate) v(vout)

  * timestep for exact simulation results
  * tran 5ps 0.5us

  * timestep for faster simulation results
  tran 50ps 0.5us

  remzerovec
  write pfd_charge_pump_10.raw
  set appendwrite

.endc

"


v(vout)="0.0

.control
  save all

  * timestep for exact simulation results
  tran 5ps 0.5us

  * timestep for faster simulation results
  * tran 50ps 0.5us

  remzerovec
  write pfd_charge_pump_10.raw
  set appA}
C {devices/lab_pin.sym} 2370 -2850 0 0 {name=p20 lab=F_VCO
value="

.include /foss/pdks/sky130A/libs.ref/sky130_fd_sc_hd/spice/sky130_fd_sc_hd.spice

.option method=gear
.option wnflag=1

* V_out initial voltage value for the F_VCO delay of 2ns  (leading)
* .ic v(vout) = 1.8

* V_out initial voltage value for the F_VCO delay of 12ns (lock condition)
.ic v(vout) = 0.83

* V_out initial voltage value for the F_VCO delay of 22ns (lagging)
* .ic v(vout) = 0

.control
  save v(f_ref) save v(f_vco) save v(i_in) save v(up_pfd) v(down_pfd) v(up_pfd_b) v(down_pfd_b) v(up) v(up_b) v(down) v(down_b) v(x) v(opamp_out) v(up_input) v(down_input) v(down_gate) v(vout)

  * timestep for exact simulation results
  * tran 5ps 0.5us

  * timestep for faster simulation results
  tran 50ps 0.5us

  remzerovec
  write pfd_charge_pump_10.raw
  set appendwrite

.endc

"


v(vout)="0.0

.control
  save all

  * timestep for exact simulation results
  tran 5ps 0.5us

  * timestep for faster simulation results
  * tran 50ps 0.5us

  remzerovec
  write pfd_charge_pump_10.raw
  set appA}
C {devices/isource.sym} 2220 -3360 2 0 {name=I1 value=100u}
C {devices/gnd.sym} 2220 -3330 0 0 {name=l26 lab=GND}
C {devices/lab_pin.sym} 2220 -3430 2 1 {name=p3 sig_type=std_logic lab=I_IN}
C {devices/lab_pin.sym} 2370 -2820 2 1 {name=p1 sig_type=std_logic lab=I_IN}
C {devices/vdd.sym} 2470 -2920 0 1 {name=l32 lab=VDD
value="

.include /foss/pdks/sky130A/libs.ref/sky130_fd_sc_hd/spice/sky130_fd_sc_hd.spice

.option method=gear
.option wnflag=1

* V_out initial voltage value for the F_VCO delay of 2ns  (leading)
* .ic v(vout) = 1.8

* V_out initial voltage value for the F_VCO delay of 12ns (lock condition)
.ic v(vout) = 0.83

* V_out initial voltage value for the F_VCO delay of 22ns (lagging)
* .ic v(vout) = 0

.control
  save v(f_ref) save v(f_vco) save v(i_in) save v(up_pfd) v(down_pfd) v(up_pfd_b) v(down_pfd_b) v(up) v(up_b) v(down) v(down_b) v(x) v(opamp_out) v(up_input) v(down_input) v(down_gate) v(vout)

  * timestep for exact simulation results
  * tran 5ps 0.5us

  * timestep for faster simulation results
  tran 50ps 0.5us

  remzerovec
  write pfd_charge_pump_10.raw
  set appendwrite

.endc

"


v(vout)="0.0

.control
  save all

  * timestep for exact simulation results
  tran 5ps 0.5us

  * timestep for faster simulation results
  * tran 50ps 0.5us

  remzerovec
  write pfd_charge_pump_10.raw
  set appendA}
C {devices/gnd.sym} 2470 -2780 0 0 {name=l33 lab=GND
value="

.include /foss/pdks/sky130A/libs.ref/sky130_fd_sc_hd/spice/sky130_fd_sc_hd.spice

.option method=gear
.option wnflag=1

* V_out initial voltage value for the F_VCO delay of 2ns  (leading)
* .ic v(vout) = 1.8

* V_out initial voltage value for the F_VCO delay of 12ns (lock condition)
.ic v(vout) = 0.83

* V_out initial voltage value for the F_VCO delay of 22ns (lagging)
* .ic v(vout) = 0

.control
  save v(f_ref) save v(f_vco) save v(i_in) save v(up_pfd) v(down_pfd) v(up_pfd_b) v(down_pfd_b) v(up) v(up_b) v(down) v(down_b) v(x) v(opamp_out) v(up_input) v(down_input) v(down_gate) v(vout)

  * timestep for exact simulation results
  * tran 5ps 0.5us

  * timestep for faster simulation results
  tran 50ps 0.5us

  remzerovec
  write pfd_charge_pump_10.raw
  set appendwrite

.endc

"}
C {devices/lab_pin.sym} 2570 -2850 2 0 {name=p26 sig_type=std_logic lab=VOUT}
C {devices/gnd.sym} 2710 -2690 0 0 {name=l1 lab=GND
value="

.include /foss/pdks/sky130A/libs.ref/sky130_fd_sc_hd/spice/sky130_fd_sc_hd.spice

.option method=gear
.option wnflag=1

* V_out initial voltage value for the F_VCO delay of 2ns  (leading)
* .ic v(vout) = 1.8

* V_out initial voltage value for the F_VCO delay of 12ns (lock condition)
.ic v(vout) = 0.83

* V_out initial voltage value for the F_VCO delay of 22ns (lagging)
* .ic v(vout) = 0

.control
  save v(f_ref) save v(f_vco) save v(i_in) save v(up_pfd) v(down_pfd) v(up_pfd_b) v(down_pfd_b) v(up) v(up_b) v(down) v(down_b) v(x) v(opamp_out) v(up_input) v(down_input) v(down_gate) v(vout)

  * timestep for exact simulation results
  * tran 5ps 0.5us

  * timestep for faster simulation results
  tran 50ps 0.5us

  remzerovec
  write pfd_charge_pump_10.raw
  set appendwrite

.endc

"}
C {/foss/designs/my_design/projects/pll/charge_pump/xschem_ngspice/loop_filter_xschem.sym} 2710 -2770 0 0 {name=x1}
C {/foss/designs/my_design/projects/pll/charge_pump/magic/pfd_cp_magic.sym} 2470 -2850 0 0 {name=x2}
